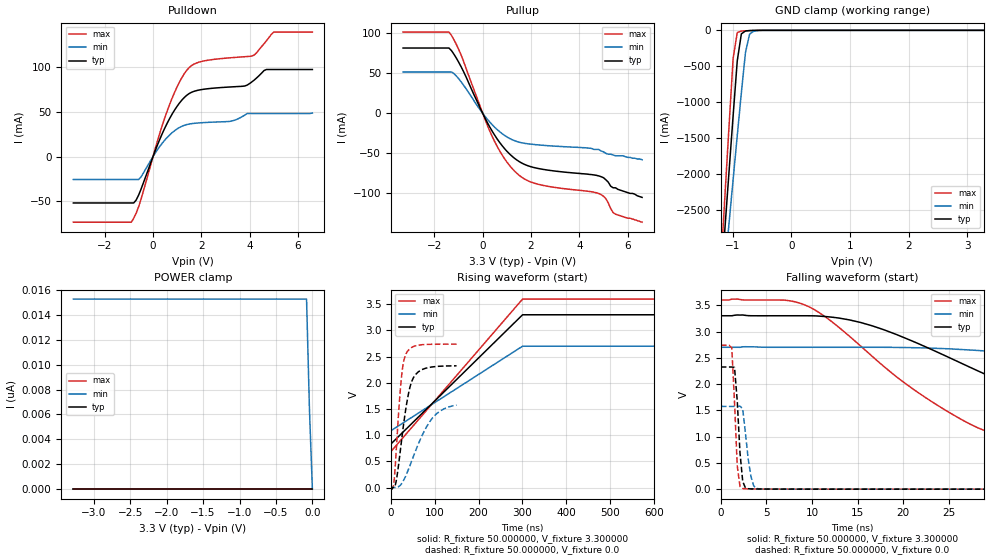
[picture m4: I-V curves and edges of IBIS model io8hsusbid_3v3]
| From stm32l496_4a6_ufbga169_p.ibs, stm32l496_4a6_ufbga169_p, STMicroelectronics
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|   Model io8hsusbid_3v3
[Model]  io8hsusbid_3v3
Model_type I/O
Polarity   Non-Inverting
Enable   Active-Low
Vinl =   0.990000V
Vinh =   2.310000V
Vmeas =  1.650000V
Cref =   100.000000nF
Rref =   1.000000k
Vref =   3.300000V
C_comp   2.116400pF   2.092700pF   2.152900pF
[Temperature Range]   25.000000   0.125000k   -40.000000
[Pullup Reference]   3.300000V   2.700000V   3.600000V
[Pulldown Reference]   0.0V   0.0V   0.0V
[POWER Clamp Reference]   3.300000V   2.700000V   3.600000V
[GND Clamp Reference]   0.0V   0.0V   0.0V
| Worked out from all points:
|   slope of the pulldown table from 0 to 0.495 V, typ, clamps not added: 15.4 ohm
|   slope of the pullup table from 0 to 0.495 V, typ, clamps not added: 18.1 ohm
|   GND clamp passes 1 mA (typ) near -0.59 V on its own axis
|   rising waveform, R_fixture 50.000000, V_fixture 3.300000: 20-80 % time 180ns typ, 180ns min, 180ns max; typ from 0.835 V to 3.3 V
|   rising waveform, R_fixture 50.000000, V_fixture 0.0: 20-80 % time 23.9ns typ, 50.4ns min, 14.3ns max; typ from 0 V to 2.33 V
|   falling waveform, R_fixture 50.000000, V_fixture 3.300000: 20-80 % time 21ns typ, 41.6ns min, 13.6ns max; typ from 3.3 V to 0.835 V
|   falling waveform, R_fixture 50.000000, V_fixture 0.0: 20-80 % time 510ps typ, 662ps min, 429ps max; typ from 2.33 V to 0 V
[Pulldown]
|Voltage   I(typ)   I(min)   I(max)
-3.3V     -51.62mA   -25.53mA   -73.04mA
-900mV    -51.62mA   -25.53mA   -73.04mA
-500mV    -36.51mA   -22.79mA   -47.71mA
200mV     14.03mA    8.316mA    18.9mA
700mV     42.99mA    24.4mA     58.9mA
1.2V      63.06mA    33.8mA     88.14mA
1.6V      71.64mA    36.67mA    101.4mA
3.2V      77.51mA    39.29mA    110mA
4.1V      83.27mA    47.98mA    111.9mA
4.6V      95.83mA    47.98mA    125.7mA
5V        96.94mA    47.98mA    138.6mA
6.6V      96.94mA    48.43mA    138.6mA
[Pullup]
|Voltage   I(typ)   I(min)   I(max)
-3.3V     81.68mA    51.74mA    101.6mA
-1.4V     81.68mA    51.74mA    101.6mA
-900mV    58.51mA    39.6mA     73.28mA
100mV     -6.165mA   -3.962mA   -8.038mA
500mV     -27.53mA   -17.49mA   -35.6mA
1V        -47.29mA   -29.38mA   -60.81mA
1.5V      -60.05mA   -35.95mA   -77.15mA
2.4V      -69.45mA   -39.66mA   -89.34mA
4.8V      -78.1mA    -45mA      -100.1mA
5.1V      -83mA      -50mA      -106.7mA
5.5V      -93mA      -53mA      -126mA
6.6V      -105mA     -58mA      -136mA
[GND_clamp]
|Voltage   I(typ)   I(min)   I(max)
-3.3V     -9.914A    -9.595A    -9.188A
-1.2V     -3.541A    -3.911A    -3.279A
-1.13V    -2.75A     -3.295A    -2.301A
-1.06V    -1.963A    -2.68A     -1.33A
-990mV    -1.183A    -2.069A    -386.7mA
-920mV    -424.7mA   -1.463A    -31.42mA
-850mV    -49.12mA   -868.7mA   -10.48mA
-780mV    -9.121mA   -308.3mA   -6.715mA
-710mV    -3.648mA   -53.81mA   -3.986mA
-640mV    -1.726mA   -11.03mA   -1.885mA
-430mV    -22.46uA   -116.8uA   -9.748uA
3.28V     0A         0A         0A
[POWER_clamp]
|Voltage   I(typ)   I(min)   I(max)
-3.28V    0A         15.27nA    0A
-80mV     0A         15.27nA    0A
-40mV     0A         6.354nA    0A
0V        0A         0A         0A
[Ramp]
| variable   typ   min   max
dV/dt_r  1.39476/23.89676n   0.94506/53.25050n   1.64316/14.30463n
dV/dt_f  1.47899/21.07093n   0.96780/44.63517n   1.74604/13.57871n
R_load = 50.000000
[Rising Waveform]
R_fixture= 50.000000
V_fixture= 3.300000
V_fixture_min= 2.700000
V_fixture_max= 3.600000
|time   V(typ)   V(min)   V(max)
0s        835mV      1.087V     689.9mV
300.3ns   3.3V       2.7V       3.6V
600.6ns   3.3V       2.7V       3.6V
29.73us   3.3V       2.7V       3.6V
[Rising Waveform]
R_fixture= 50.000000
V_fixture= 0.0
V_fixture_min= 0.0
V_fixture_max= 0.0
|time   V(typ)   V(min)   V(max)
0s        3.26nV     60.03nV    3.11nV
6.306ns   2.705mV    -147.5uV   82.32mV
12.01ns   141.3mV    1.947mV    747.6mV
18.32ns   516.3mV    25.36mV    1.571V
23.72ns   889.5mV    70.29mV    2.109V
33.93ns   1.521V     231.3mV    2.552V
45.05ns   1.975V     463.5mV    2.664V
61.86ns   2.208V     824.6mV    2.718V
98.5ns    2.307V     1.367V     2.737V
149.5ns   2.325V     1.575V     2.739V
[Falling Waveform]
R_fixture= 50.000000
V_fixture= 3.300000
V_fixture_min= 2.700000
V_fixture_max= 3.600000
|time   V(typ)   V(min)   V(max)
0s        3.3V       2.7V       3.6V
9.61ns    3.3V       2.7V       3.476V
16.52ns   3.113V     2.7V       2.541V
24.92ns   2.513V     2.672V     1.471V
29.73ns   2.129V     2.619V     1.061V
34.53ns   1.78V      2.543V     888.3mV
45.35ns   1.198V     2.309V     774.6mV
57.66ns   992.8mV    1.996V     728.6mV
92.79ns   866.9mV    1.304V     696mV
149.5ns   835mV      1.087V     689.9mV
[Falling Waveform]
R_fixture= 50.000000
V_fixture= 0.0
V_fixture_min= 0.0
V_fixture_max= 0.0
|time   V(typ)   V(min)   V(max)
0s        2.325V     1.575V     2.739V
1.201ns   2.324V     1.575V     2.691V
1.502ns   2.318V     1.575V     1.659V
1.802ns   1.677V     1.575V     443.2mV
2.102ns   691.1mV    1.581V     52.84mV
2.402ns   145mV      1.526V     12.56mV
2.703ns   24.02mV    1.062V     6.825mV
3.604ns   4.078mV    64.23mV    3.938mV
4.505ns   2.435mV    3.996mV    2.725mV
149.5ns   3.26nV     60.03nV    3.11nV
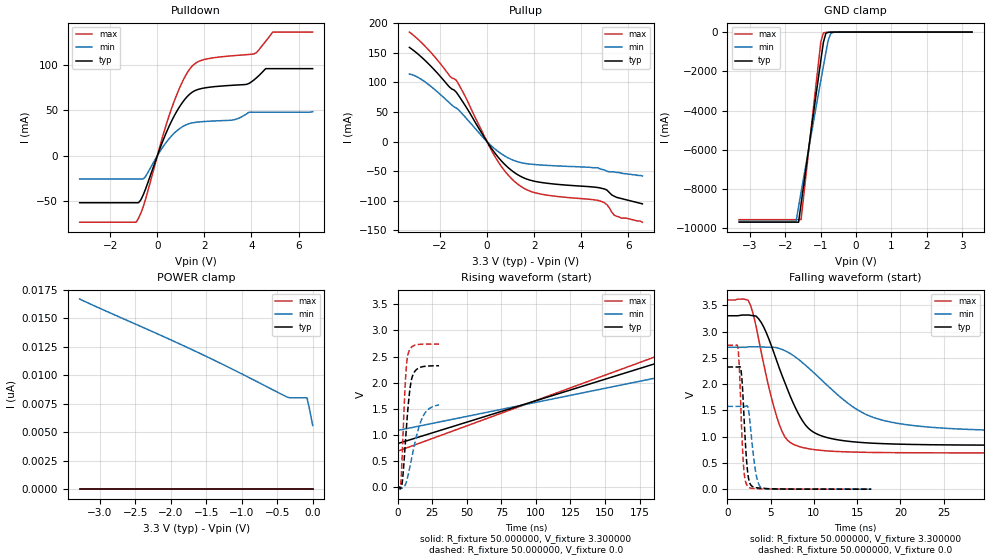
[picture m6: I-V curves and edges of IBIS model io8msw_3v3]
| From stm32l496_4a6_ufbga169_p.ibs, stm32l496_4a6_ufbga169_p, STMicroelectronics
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|   Model io8msw_3v3
[Model]  io8msw_3v3
Model_type I/O
Polarity   Non-Inverting
Enable   Active-Low
Vinl =   0.990000V
Vinh =   2.310000V
Vmeas =  1.650000V
Cref =   100.000000nF
Rref =   1.000000k
Vref =   3.300000V
C_comp   2.968600pF   2.938100pF   3.196200pF
[Temperature Range]   25.000000   0.125000k   -40.000000
[Pullup Reference]   3.300000V   2.700000V   3.600000V
[Pulldown Reference]   0.0V   0.0V   0.0V
[POWER Clamp Reference]   3.300000V   2.700000V   3.600000V
[GND Clamp Reference]   0.0V   0.0V   0.0V
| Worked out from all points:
|   slope of the pulldown table from 0 to 0.495 V, typ, clamps not added: 15.4 ohm
|   slope of the pullup table from 0 to 0.495 V, typ, clamps not added: 18.1 ohm
|   GND clamp passes 1 mA (typ) near -0.58 V on its own axis
|   rising waveform, R_fixture 50.000000, V_fixture 3.300000: 20-80 % time 180ns typ, 180ns min, 180ns max; typ from 0.835 V to 3.3 V
|   rising waveform, R_fixture 50.000000, V_fixture 0.0: 20-80 % time 4.25ns typ, 8.51ns min, 2.79ns max; typ from 0 V to 2.33 V
|   falling waveform, R_fixture 50.000000, V_fixture 3.300000: 20-80 % time 3.68ns typ, 7.29ns min, 2.5ns max; typ from 3.3 V to 0.835 V
|   falling waveform, R_fixture 50.000000, V_fixture 0.0: 20-80 % time 488ps typ, 660ps min, 410ps max; typ from 2.33 V to 0 V
[Pulldown]
|Voltage   I(typ)   I(min)   I(max)
-3.3V     -51.62mA   -25.53mA   -73.04mA
-900mV    -51.62mA   -25.53mA   -73.04mA
-500mV    -36.51mA   -22.79mA   -47.71mA
200mV     14.03mA    8.316mA    18.9mA
700mV     42.99mA    24.4mA     58.9mA
1.2V      63.06mA    33.8mA     88.14mA
1.6V      71.64mA    36.67mA    101.4mA
3.2V      77.51mA    39.29mA    110mA
4.1V      83.27mA    47.97mA    111.9mA
4.6V      95.8mA     47.97mA    125.7mA
4.9V      95.8mA     47.97mA    136mA
6.6V      95.8mA     48.43mA    136mA
[Pullup]
|Voltage   I(typ)   I(min)   I(max)
-3.3V     159.3mA    114.2mA    185.2mA
-2.6V     135.9mA    99.98mA    159.9mA
-1.6V     92.46mA    65.72mA    111.7mA
-1.3V     83.3mA     56.77mA    103.4mA
300mV     -17.49mA   -11.19mA   -22.71mA
800mV     -40.27mA   -25.28mA   -51.87mA
1.3V      -55.74mA   -33.93mA   -71.59mA
2.2V      -68.23mA   -39.11mA   -87.81mA
4.8V      -78.1mA    -46mA      -100.2mA
5.1V      -82mA      -50mA      -106.7mA
5.5V      -94mA      -52mA      -126mA
6.6V      -105mA     -58mA      -136mA
[GND_clamp]
|Voltage   I(typ)   I(min)   I(max)
-3.3V     -9.687A    -9.633A    -9.557A
-1.69V    -9.687A    -9.633A    -9.557A
-1.62V    -9.687A    -8.894A    -9.557A
-1.55V    -8.764A    -8.167A    -9.557A
-1.13V    -3.236A    -3.867A    -2.713A
-990mV    -1.416A    -2.448A    -480.1mA
-920mV    -530mA     -1.746A    -39.96mA
-850mV    -62.36mA   -1.055A    -14.04mA
-780mV    -12.04mA   -390.4mA   -9.013mA
-710mV    -4.897mA   -69.08mA   -5.32mA
-640mV    -2.305mA   -14.59mA   -2.498mA
3.28V     0A         0A         0A
[POWER_clamp]
|Voltage   I(typ)   I(min)   I(max)
-3.28V    0A         16.68nA    0A
-1.64V    0A         12.07nA    0A
-1.08V    0A         10.37nA    0A
-360mV    0A         8.078nA    0A
-320mV    0A         8.02nA     0A
-80mV     0A         8.02nA     0A
-40mV     0A         6.883nA    0A
0V        0A         5.582nA    0A
[Ramp]
| variable   typ   min   max
dV/dt_r  1.37874/4.16820n   0.74394/6.13098n   1.64118/2.77639n
dV/dt_f  1.45454/3.56865n   0.79542/5.42365n   1.74082/2.48210n
R_load = 50.000000
[Rising Waveform]
R_fixture= 50.000000
V_fixture= 3.300000
V_fixture_min= 2.700000
V_fixture_max= 3.600000
|time   V(typ)   V(min)   V(max)
0s        835mV      1.087V     689.9mV
300.3ns   3.3V       2.7V       3.6V
600.6ns   3.3V       2.7V       3.6V
29.73us   3.3V       2.7V       3.6V
[Rising Waveform]
R_fixture= 50.000000
V_fixture= 0.0
V_fixture_min= 0.0
V_fixture_max= 0.0
|time   V(typ)   V(min)   V(max)
0s        3.841nV    97.75nV    3.582nV
2.222ns   -19.96mV   184.3uV    67.15mV
3.544ns   159.7mV    -6.967mV   818.5mV
5.526ns   853.9mV    50.68mV    2.023V
6.547ns   1.232V     129mV      2.395V
7.748ns   1.613V     258.3mV    2.573V
10.51ns   2.114V     611.9mV    2.692V
17.24ns   2.301V     1.295V     2.736V
21.44ns   2.318V     1.475V     2.738V
29.91ns   2.325V     1.575V     2.739V
[Falling Waveform]
R_fixture= 50.000000
V_fixture= 3.300000
V_fixture_min= 2.700000
V_fixture_max= 3.600000
|time   V(typ)   V(min)   V(max)
0s        3.3V       2.7V       3.6V
2.703ns   3.308V     2.711V     3.484V
4.204ns   3.081V     2.704V     2.374V
5.405ns   2.58V      2.699V     1.544V
6.607ns   2.041V     2.638V     1.003V
8.408ns   1.374V     2.444V     805.3mV
10.21ns   1.061V     2.182V     749.3mV
16.52ns   877.4mV    1.386V     699.5mV
26.43ns   841mV      1.148V     690.7mV
149.5ns   835mV      1.087V     689.9mV
[Falling Waveform]
R_fixture= 50.000000
V_fixture= 0.0
V_fixture_min= 0.0
V_fixture_max= 0.0
|time   V(typ)   V(min)   V(max)
0s        2.325V     1.575V     2.739V
1.201ns   2.324V     1.575V     2.696V
1.368ns   2.33V      1.575V     2.34V
1.568ns   2.263V     1.575V     1.471V
1.869ns   1.526V     1.575V     425.2mV
2.135ns   719.1mV    1.582V     121.9mV
2.369ns   279.5mV    1.556V     48.26mV
3.237ns   30.9mV     352.2mV    10.55mV
3.871ns   19.4mV     33.64mV    5.313mV
16.62ns   3.841nV    97.75nV    3.582nV
